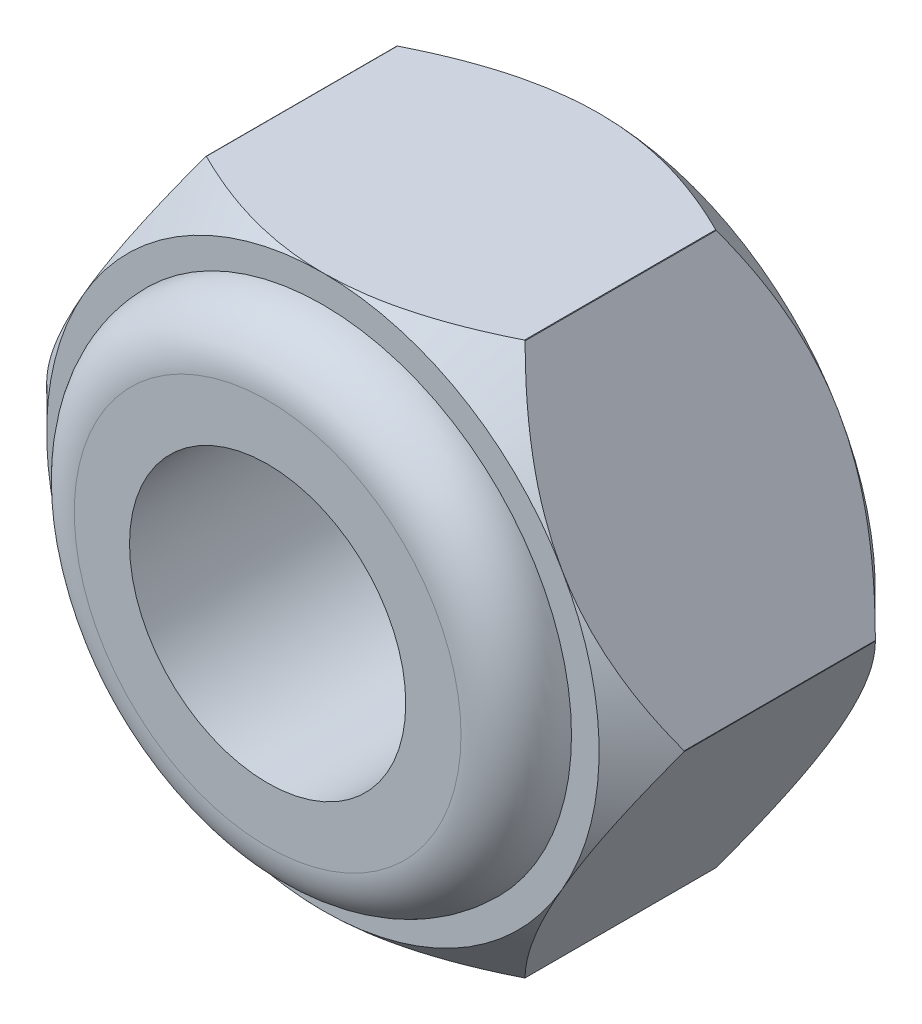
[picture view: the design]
ISO-10303-21;
HEADER;
FILE_DESCRIPTION(('STEP AP214'),'2;1');
FILE_NAME('part.step','',(''),(''),'','','');
FILE_SCHEMA(('AUTOMOTIVE_DESIGN { 1 0 10303 214 1 1 1 1 }'));
ENDSEC;
DATA;
#1=APPLICATION_CONTEXT('core data for automotive mechanical design processes');
#2=APPLICATION_PROTOCOL_DEFINITION('international standard','automotive_design',2000,#1);
#3=PRODUCT_CONTEXT('',#1,'mechanical');
#4=PRODUCT('Part','Part','',(#3));
#5=PRODUCT_RELATED_PRODUCT_CATEGORY('part','',(#4));
#6=PRODUCT_DEFINITION_FORMATION('','',#4);
#7=PRODUCT_DEFINITION_CONTEXT('part definition',#1,'design');
#8=PRODUCT_DEFINITION('design','',#6,#7);
#9=PRODUCT_DEFINITION_SHAPE('','',#8);
#10=(LENGTH_UNIT() NAMED_UNIT(*) SI_UNIT(.MILLI.,.METRE.));
#11=(NAMED_UNIT(*) PLANE_ANGLE_UNIT() SI_UNIT($,.RADIAN.));
#12=(NAMED_UNIT(*) SI_UNIT($,.STERADIAN.) SOLID_ANGLE_UNIT());
#13=UNCERTAINTY_MEASURE_WITH_UNIT(LENGTH_MEASURE(1.E-05),#10,'distance_accuracy_value','');
#14=(GEOMETRIC_REPRESENTATION_CONTEXT(3) GLOBAL_UNCERTAINTY_ASSIGNED_CONTEXT((#13)) GLOBAL_UNIT_ASSIGNED_CONTEXT((#10,
#11,#12)) REPRESENTATION_CONTEXT('',''));
#15=CARTESIAN_POINT('',(0.,0.,0.));
#16=DIRECTION('',(0.,0.,1.));
#17=DIRECTION('',(1.,0.,0.));
#18=AXIS2_PLACEMENT_3D('',#15,#16,#17);
#19=CARTESIAN_POINT('',(0.,0.,5.));
#20=DIRECTION('',(0.,0.,-1.));
#21=DIRECTION('',(-1.,0.,0.));
#22=AXIS2_PLACEMENT_3D('',#19,#20,#21);
#23=CYLINDRICAL_SURFACE('',#22,5.77);
#24=DIRECTION('',(0.,0.,-1.));
#25=VECTOR('',#24,1.);
#26=CARTESIAN_POINT('',(-2.89025723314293,4.99392762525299,5.));
#27=LINE('',#26,#25);
#28=CARTESIAN_POINT('',(-2.89025723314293,4.99392762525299,4.22999999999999));
#29=VERTEX_POINT('',#28);
#30=CARTESIAN_POINT('',(-2.89025723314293,4.99392762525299,0.770000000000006));
#31=VERTEX_POINT('',#30);
#32=EDGE_CURVE('E378',#29,#31,#27,.T.);
#33=ORIENTED_EDGE('',*,*,#32,.F.);
#34=CARTESIAN_POINT('',(0.,0.,4.22999999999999));
#35=DIRECTION('',(0.,0.,1.));
#36=DIRECTION('',(1.,0.,0.));
#37=AXIS2_PLACEMENT_3D('',#34,#35,#36);
#38=CIRCLE('',#37,5.77);
#39=CARTESIAN_POINT('',(-2.87973957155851,5.,4.22999999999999));
#40=VERTEX_POINT('',#39);
#41=EDGE_CURVE('E367',#29,#40,#38,.F.);
#42=ORIENTED_EDGE('',*,*,#41,.T.);
#43=DIRECTION('',(0.,0.,-1.));
#44=VECTOR('',#43,1.);
#45=CARTESIAN_POINT('',(-2.87973957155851,5.,5.));
#46=LINE('',#45,#44);
#47=CARTESIAN_POINT('',(-2.87973957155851,5.,0.770000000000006));
#48=VERTEX_POINT('',#47);
#49=EDGE_CURVE('E54',#48,#40,#46,.F.);
#50=ORIENTED_EDGE('',*,*,#49,.F.);
#51=CARTESIAN_POINT('',(0.,0.,0.770000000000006));
#52=DIRECTION('',(0.,0.,1.));
#53=DIRECTION('',(1.,0.,0.));
#54=AXIS2_PLACEMENT_3D('',#51,#52,#53);
#55=CIRCLE('',#54,5.77);
#56=EDGE_CURVE('E340',#48,#31,#55,.T.);
#57=ORIENTED_EDGE('',*,*,#56,.T.);
#58=EDGE_LOOP('',(#33,#42,#50,#57));
#59=FACE_BOUND('',#58,.T.);
#60=ADVANCED_FACE('F32',(#59),#23,.T.);
#61=DIRECTION('',(0.,0.,-1.));
#62=VECTOR('',#61,1.);
#63=CARTESIAN_POINT('',(-5.76999680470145,0.00607237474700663,5.));
#64=LINE('',#63,#62);
#65=CARTESIAN_POINT('',(-5.76999680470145,0.00607237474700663,0.770000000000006));
#66=VERTEX_POINT('',#65);
#67=CARTESIAN_POINT('',(-5.76999680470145,0.00607237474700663,4.22999999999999));
#68=VERTEX_POINT('',#67);
#69=EDGE_CURVE('E282',#66,#68,#64,.F.);
#70=ORIENTED_EDGE('',*,*,#69,.F.);
#71=CARTESIAN_POINT('',(-5.76999680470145,-0.00607237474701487,0.770000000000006));
#72=VERTEX_POINT('',#71);
#73=EDGE_CURVE('E345',#66,#72,#55,.T.);
#74=ORIENTED_EDGE('',*,*,#73,.T.);
#75=DIRECTION('',(0.,0.,-1.));
#76=VECTOR('',#75,1.);
#77=CARTESIAN_POINT('',(-5.76999680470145,-0.00607237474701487,5.));
#78=LINE('',#77,#76);
#79=CARTESIAN_POINT('',(-5.76999680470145,-0.00607237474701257,4.22999999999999));
#80=VERTEX_POINT('',#79);
#81=EDGE_CURVE('E231',#80,#72,#78,.T.);
#82=ORIENTED_EDGE('',*,*,#81,.F.);
#83=EDGE_CURVE('E177',#80,#68,#38,.F.);
#84=ORIENTED_EDGE('',*,*,#83,.T.);
#85=EDGE_LOOP('',(#70,#74,#82,#84));
#86=FACE_BOUND('',#85,.T.);
#87=ADVANCED_FACE('F399',(#86),#23,.T.);
#88=DIRECTION('',(0.,0.,-1.));
#89=VECTOR('',#88,1.);
#90=CARTESIAN_POINT('',(2.87973957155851,5.,5.));
#91=LINE('',#90,#89);
#92=CARTESIAN_POINT('',(2.87973957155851,5.,4.22999999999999));
#93=VERTEX_POINT('',#92);
#94=CARTESIAN_POINT('',(2.87973957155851,5.,0.770000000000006));
#95=VERTEX_POINT('',#94);
#96=EDGE_CURVE('E281',#93,#95,#91,.T.);
#97=ORIENTED_EDGE('',*,*,#96,.F.);
#98=CARTESIAN_POINT('',(2.89025723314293,4.99392762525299,4.22999999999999));
#99=VERTEX_POINT('',#98);
#100=EDGE_CURVE('E316',#93,#99,#38,.F.);
#101=ORIENTED_EDGE('',*,*,#100,.T.);
#102=DIRECTION('',(0.,0.,-1.));
#103=VECTOR('',#102,1.);
#104=CARTESIAN_POINT('',(2.89025723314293,4.99392762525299,5.));
#105=LINE('',#104,#103);
#106=CARTESIAN_POINT('',(2.89025723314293,4.99392762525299,0.770000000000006));
#107=VERTEX_POINT('',#106);
#108=EDGE_CURVE('E46',#107,#99,#105,.F.);
#109=ORIENTED_EDGE('',*,*,#108,.F.);
#110=EDGE_CURVE('E335',#107,#95,#55,.T.);
#111=ORIENTED_EDGE('',*,*,#110,.T.);
#112=EDGE_LOOP('',(#97,#101,#109,#111));
#113=FACE_BOUND('',#112,.T.);
#114=ADVANCED_FACE('F448',(#113),#23,.T.);
#115=DIRECTION('',(0.,0.,-1.));
#116=VECTOR('',#115,1.);
#117=CARTESIAN_POINT('',(5.76999680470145,0.00607237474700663,5.));
#118=LINE('',#117,#116);
#119=CARTESIAN_POINT('',(5.76999680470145,0.0060723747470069,4.22999999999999));
#120=VERTEX_POINT('',#119);
#121=CARTESIAN_POINT('',(5.76999680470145,0.00607237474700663,0.770000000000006));
#122=VERTEX_POINT('',#121);
#123=EDGE_CURVE('E402',#120,#122,#118,.T.);
#124=ORIENTED_EDGE('',*,*,#123,.F.);
#125=CARTESIAN_POINT('',(5.76999680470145,-0.00607237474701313,4.22999999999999));
#126=VERTEX_POINT('',#125);
#127=EDGE_CURVE('E358',#120,#126,#38,.F.);
#128=ORIENTED_EDGE('',*,*,#127,.T.);
#129=DIRECTION('',(0.,0.,-1.));
#130=VECTOR('',#129,1.);
#131=CARTESIAN_POINT('',(5.76999680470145,-0.00607237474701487,5.));
#132=LINE('',#131,#130);
#133=CARTESIAN_POINT('',(5.76999680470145,-0.00607237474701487,0.770000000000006));
#134=VERTEX_POINT('',#133);
#135=EDGE_CURVE('E410',#134,#126,#132,.F.);
#136=ORIENTED_EDGE('',*,*,#135,.F.);
#137=EDGE_CURVE('E341',#134,#122,#55,.T.);
#138=ORIENTED_EDGE('',*,*,#137,.T.);
#139=EDGE_LOOP('',(#124,#128,#136,#138));
#140=FACE_BOUND('',#139,.T.);
#141=ADVANCED_FACE('F454',(#140),#23,.T.);
#142=DIRECTION('',(0.,0.,-1.));
#143=VECTOR('',#142,1.);
#144=CARTESIAN_POINT('',(2.89025723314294,-4.99392762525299,5.));
#145=LINE('',#144,#143);
#146=CARTESIAN_POINT('',(2.89025723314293,-4.99392762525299,4.22999999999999));
#147=VERTEX_POINT('',#146);
#148=CARTESIAN_POINT('',(2.89025723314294,-4.99392762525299,0.770000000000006));
#149=VERTEX_POINT('',#148);
#150=EDGE_CURVE('E407',#147,#149,#145,.T.);
#151=ORIENTED_EDGE('',*,*,#150,.F.);
#152=CARTESIAN_POINT('',(2.87973957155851,-5.,4.22999999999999));
#153=VERTEX_POINT('',#152);
#154=EDGE_CURVE('E349',#147,#153,#38,.F.);
#155=ORIENTED_EDGE('',*,*,#154,.T.);
#156=DIRECTION('',(0.,0.,-1.));
#157=VECTOR('',#156,1.);
#158=CARTESIAN_POINT('',(2.87973957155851,-5.,5.));
#159=LINE('',#158,#157);
#160=CARTESIAN_POINT('',(2.87973957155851,-5.,0.770000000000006));
#161=VERTEX_POINT('',#160);
#162=EDGE_CURVE('E233',#161,#153,#159,.F.);
#163=ORIENTED_EDGE('',*,*,#162,.F.);
#164=EDGE_CURVE('E348',#161,#149,#55,.T.);
#165=ORIENTED_EDGE('',*,*,#164,.T.);
#166=EDGE_LOOP('',(#151,#155,#163,#165));
#167=FACE_BOUND('',#166,.T.);
#168=ADVANCED_FACE('F450',(#167),#23,.T.);
#169=DIRECTION('',(0.,0.,-1.));
#170=VECTOR('',#169,1.);
#171=CARTESIAN_POINT('',(-2.87973957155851,-5.,5.));
#172=LINE('',#171,#170);
#173=CARTESIAN_POINT('',(-2.87973957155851,-5.,4.22999999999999));
#174=VERTEX_POINT('',#173);
#175=CARTESIAN_POINT('',(-2.87973957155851,-5.,0.770000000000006));
#176=VERTEX_POINT('',#175);
#177=EDGE_CURVE('E415',#174,#176,#172,.T.);
#178=ORIENTED_EDGE('',*,*,#177,.F.);
#179=CARTESIAN_POINT('',(-2.89025723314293,-4.99392762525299,4.22999999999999));
#180=VERTEX_POINT('',#179);
#181=EDGE_CURVE('E357',#174,#180,#38,.F.);
#182=ORIENTED_EDGE('',*,*,#181,.T.);
#183=DIRECTION('',(0.,0.,-1.));
#184=VECTOR('',#183,1.);
#185=CARTESIAN_POINT('',(-2.89025723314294,-4.99392762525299,5.));
#186=LINE('',#185,#184);
#187=CARTESIAN_POINT('',(-2.89025723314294,-4.99392762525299,0.770000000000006));
#188=VERTEX_POINT('',#187);
#189=EDGE_CURVE('E161',#188,#180,#186,.F.);
#190=ORIENTED_EDGE('',*,*,#189,.F.);
#191=EDGE_CURVE('E355',#188,#176,#55,.T.);
#192=ORIENTED_EDGE('',*,*,#191,.T.);
#193=EDGE_LOOP('',(#178,#182,#190,#192));
#194=FACE_BOUND('',#193,.T.);
#195=ADVANCED_FACE('F240',(#194),#23,.T.);
#196=CARTESIAN_POINT('',(0.,0.,0.770000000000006));
#197=DIRECTION('',(0.,0.,1.));
#198=DIRECTION('',(1.,0.,0.));
#199=AXIS2_PLACEMENT_3D('',#196,#197,#198);
#200=CONICAL_SURFACE('',#199,5.77,0.785398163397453);
#201=ORIENTED_EDGE('',*,*,#73,.F.);
#202=CARTESIAN_POINT('',(-5.7702,0.0057204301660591,0.770202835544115));
#203=CARTESIAN_POINT('',(-5.72066643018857,0.0915150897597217,0.720761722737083));
#204=CARTESIAN_POINT('',(-5.67075262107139,0.177968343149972,0.672841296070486));
#205=CARTESIAN_POINT('',(-5.57009042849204,0.352320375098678,0.580503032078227));
#206=CARTESIAN_POINT('',(-5.51934160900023,0.440219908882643,0.536087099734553));
#207=CARTESIAN_POINT('',(-5.36526368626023,0.707090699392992,0.408412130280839));
#208=CARTESIAN_POINT('',(-5.26063326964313,0.888315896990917,0.331266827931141));
#209=CARTESIAN_POINT('',(-5.04964011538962,1.25376676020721,0.199176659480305));
#210=CARTESIAN_POINT('',(-4.94333082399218,1.43789985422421,0.143900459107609));
#211=CARTESIAN_POINT('',(-4.78212663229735,1.71711370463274,0.0799714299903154));
#212=CARTESIAN_POINT('',(-4.72815538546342,1.81059464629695,0.0618344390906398));
#213=CARTESIAN_POINT('',(-4.61975813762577,1.99834418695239,0.0322976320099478));
#214=CARTESIAN_POINT('',(-4.56533220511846,2.09261266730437,0.0208968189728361));
#215=CARTESIAN_POINT('',(-4.43253200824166,2.32262935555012,0.00176361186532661));
#216=CARTESIAN_POINT('',(-4.3540143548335,2.45862592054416,-0.00223001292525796));
#217=CARTESIAN_POINT('',(-4.19712243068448,2.7303707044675,0.00461104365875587));
#218=CARTESIAN_POINT('',(-4.11874821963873,2.86611882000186,0.0154509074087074));
#219=CARTESIAN_POINT('',(-3.96274074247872,3.13633169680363,0.0513199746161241));
#220=CARTESIAN_POINT('',(-3.88510839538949,3.27079486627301,0.0763649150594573));
#221=CARTESIAN_POINT('',(-3.73117872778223,3.53740887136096,0.139283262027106));
#222=CARTESIAN_POINT('',(-3.6548813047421,3.66955988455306,0.177155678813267));
#223=CARTESIAN_POINT('',(-3.51977568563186,3.90356968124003,0.254866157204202));
#224=CARTESIAN_POINT('',(-3.46066177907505,4.00595797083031,0.292618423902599));
#225=CARTESIAN_POINT('',(-3.3434891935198,4.20890684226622,0.374174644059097));
#226=CARTESIAN_POINT('',(-3.28543053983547,4.30946738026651,0.417978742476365));
#227=CARTESIAN_POINT('',(-3.17055191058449,4.50844300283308,0.510664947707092));
#228=CARTESIAN_POINT('',(-3.11372867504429,4.60686373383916,0.559531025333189));
#229=CARTESIAN_POINT('',(-3.00112820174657,4.80189347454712,0.661707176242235));
#230=CARTESIAN_POINT('',(-2.94535036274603,4.89850352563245,0.715014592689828));
#231=CARTESIAN_POINT('',(-2.89005687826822,4.99427465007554,0.770200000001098));
#232=B_SPLINE_CURVE_WITH_KNOTS('',3,(#202,#203,#204,#205,#206,#207,#208,#209,#210,#211,#212,
#213,#214,#215,#216,#217,#218,#219,#220,#221,#222,#223,#224,#225,#226,#227,#228,#229,#230,#231),
.UNSPECIFIED.,.F.,.F.,(4,2,2,2,2,2,2,2,2,2,2,2,2,2,4),(0.,0.332137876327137,0.664455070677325,
1.33265140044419,1.99029611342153,2.31847842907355,2.64661216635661,3.11713813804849,
3.58782853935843,4.05904141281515,4.53021793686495,4.90237265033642,5.27453627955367,
5.64555549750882,6.01635434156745),.UNSPECIFIED.);
#233=CARTESIAN_POINT('',(-4.33012701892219,2.5,0.));
#234=VERTEX_POINT('',#233);
#235=EDGE_CURVE('E369',#66,#234,#232,.T.);
#236=ORIENTED_EDGE('',*,*,#235,.T.);
#237=CARTESIAN_POINT('',(0.,0.,0.));
#238=DIRECTION('',(0.,0.,1.));
#239=DIRECTION('',(1.,0.,0.));
#240=AXIS2_PLACEMENT_3D('',#237,#238,#239);
#241=CIRCLE('',#240,4.99999999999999);
#242=CARTESIAN_POINT('',(-4.33012701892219,-2.5,0.));
#243=VERTEX_POINT('',#242);
#244=EDGE_CURVE('E333',#243,#234,#241,.F.);
#245=ORIENTED_EDGE('',*,*,#244,.F.);
#246=CARTESIAN_POINT('',(-2.89005687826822,-4.99427465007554,0.770200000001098));
#247=CARTESIAN_POINT('',(-2.93959036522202,-4.90848013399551,0.720759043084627));
#248=CARTESIAN_POINT('',(-2.98950409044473,-4.82202702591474,0.67283877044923));
#249=CARTESIAN_POINT('',(-3.09016611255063,-4.64767528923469,0.580500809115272));
#250=CARTESIAN_POINT('',(-3.1409148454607,-4.55977590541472,0.536085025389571));
#251=CARTESIAN_POINT('',(-3.294992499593,-4.29290558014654,0.408410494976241));
#252=CARTESIAN_POINT('',(-3.39962272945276,-4.11168070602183,0.331265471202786));
#253=CARTESIAN_POINT('',(-3.61061549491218,-3.74623051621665,0.199175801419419));
#254=CARTESIAN_POINT('',(-3.71692458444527,-3.56209777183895,0.143899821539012));
#255=CARTESIAN_POINT('',(-3.87812846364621,-3.28288446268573,0.0799710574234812));
#256=CARTESIAN_POINT('',(-3.93209960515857,-3.18940370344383,0.0618341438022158));
#257=CARTESIAN_POINT('',(-4.0404966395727,-3.00165453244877,0.032297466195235));
#258=CARTESIAN_POINT('',(-4.09492246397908,-2.9073862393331,0.0208967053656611));
#259=CARTESIAN_POINT('',(-4.22772254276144,-2.6773697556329,0.00176357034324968));
#260=CARTESIAN_POINT('',(-4.30624018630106,-2.54137320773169,-0.00223002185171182));
#261=CARTESIAN_POINT('',(-4.46313208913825,-2.26962846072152,0.00461109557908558));
#262=CARTESIAN_POINT('',(-4.54150628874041,-2.13388036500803,0.0154509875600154));
#263=CARTESIAN_POINT('',(-4.69751374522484,-1.86366752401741,0.0513201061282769));
#264=CARTESIAN_POINT('',(-4.77514608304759,-1.72920437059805,0.076365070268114));
#265=CARTESIAN_POINT('',(-4.92907573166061,-1.46259039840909,0.139283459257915));
#266=CARTESIAN_POINT('',(-5.00537314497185,-1.33043940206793,0.177155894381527));
#267=CARTESIAN_POINT('',(-5.14047897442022,-1.09642924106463,0.254866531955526));
#268=CARTESIAN_POINT('',(-5.19959309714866,-0.994040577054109,0.292618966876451));
#269=CARTESIAN_POINT('',(-5.31676610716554,-0.791090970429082,0.374175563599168));
#270=CARTESIAN_POINT('',(-5.37482496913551,-0.690530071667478,0.417979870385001));
#271=CARTESIAN_POINT('',(-5.48970400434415,-0.491553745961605,0.510666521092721));
#272=CARTESIAN_POINT('',(-5.5465274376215,-0.393132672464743,0.559532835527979));
#273=CARTESIAN_POINT('',(-5.65912829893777,-0.198102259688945,0.661709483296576));
#274=CARTESIAN_POINT('',(-5.71490632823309,-0.101491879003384,0.715017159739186));
#275=CARTESIAN_POINT('',(-5.7702,-0.00572043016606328,0.770202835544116));
#276=B_SPLINE_CURVE_WITH_KNOTS('',3,(#246,#247,#248,#249,#250,#251,#252,#253,#254,#255,#256,
#257,#258,#259,#260,#261,#262,#263,#264,#265,#266,#267,#268,#269,#270,#271,#272,#273,#274,#275),
.UNSPECIFIED.,.F.,.F.,(4,2,2,2,2,2,2,2,2,2,2,2,2,2,4),(0.,0.332137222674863,0.664453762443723,
1.33264875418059,1.99029213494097,2.31847378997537,2.64660686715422,3.11713277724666,
3.58782311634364,4.05903594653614,4.53021242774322,4.90236852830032,5.27453354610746,
5.64555413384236,6.01635434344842),.UNSPECIFIED.);
#277=EDGE_CURVE('E223',#243,#72,#276,.T.);
#278=ORIENTED_EDGE('',*,*,#277,.T.);
#279=EDGE_LOOP('',(#201,#236,#245,#278));
#280=FACE_BOUND('',#279,.T.);
#281=ADVANCED_FACE('F235',(#280),#200,.T.);
#282=CARTESIAN_POINT('',(0.,5.,0.));
#283=VERTEX_POINT('',#282);
#284=EDGE_CURVE('E338',#234,#283,#241,.F.);
#285=ORIENTED_EDGE('',*,*,#284,.F.);
#286=EDGE_CURVE('E373',#234,#31,#232,.T.);
#287=ORIENTED_EDGE('',*,*,#286,.T.);
#288=ORIENTED_EDGE('',*,*,#56,.F.);
#289=CARTESIAN_POINT('',(-6.0229983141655,5.,2.82793131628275));
#290=CARTESIAN_POINT('',(-5.87748004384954,5.,2.71599120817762));
#291=CARTESIAN_POINT('',(-5.73117753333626,5.,2.60505456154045));
#292=CARTESIAN_POINT('',(-5.43668354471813,5.,2.38564658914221));
#293=CARTESIAN_POINT('',(-5.28849162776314,5.,2.27717585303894));
#294=CARTESIAN_POINT('',(-4.98881537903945,5.,2.06238616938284));
#295=CARTESIAN_POINT('',(-4.83731446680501,5.,1.95609027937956));
#296=CARTESIAN_POINT('',(-4.53179094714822,5.,1.7471989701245));
#297=CARTESIAN_POINT('',(-4.37776851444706,5.,1.64460329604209));
#298=CARTESIAN_POINT('',(-4.05692316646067,5.,1.43759704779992));
#299=CARTESIAN_POINT('',(-3.88990763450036,5.,1.33348351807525));
#300=CARTESIAN_POINT('',(-3.55195456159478,5.,1.13172056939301));
#301=CARTESIAN_POINT('',(-3.38101636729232,5.,1.03407223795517));
#302=CARTESIAN_POINT('',(-3.03517153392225,5.,0.847319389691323));
#303=CARTESIAN_POINT('',(-2.86027854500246,5.,0.75818979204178));
#304=CARTESIAN_POINT('',(-2.5055493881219,5.,0.590471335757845));
#305=CARTESIAN_POINT('',(-2.32571560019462,5.,0.51187750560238));
#306=CARTESIAN_POINT('',(-1.97870613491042,5.,0.375168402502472));
#307=CARTESIAN_POINT('',(-1.81202993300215,5.,0.315798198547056));
#308=CARTESIAN_POINT('',(-1.47443232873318,5.,0.210399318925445));
#309=CARTESIAN_POINT('',(-1.3035106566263,5.,0.164371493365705));
#310=CARTESIAN_POINT('',(-0.961419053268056,5.,0.0889155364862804));
#311=CARTESIAN_POINT('',(-0.790316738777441,5.,0.0591860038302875));
#312=CARTESIAN_POINT('',(-0.44598784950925,5.,0.0169466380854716));
#313=CARTESIAN_POINT('',(-0.272761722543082,5.,0.00443323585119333));
#314=CARTESIAN_POINT('',(0.0664794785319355,5.,-0.00230866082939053));
#315=CARTESIAN_POINT('',(0.232479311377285,5.,0.00268865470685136));
#316=CARTESIAN_POINT('',(0.563182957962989,5.,0.0289153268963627));
#317=CARTESIAN_POINT('',(0.727886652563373,5.,0.0501461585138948));
#318=CARTESIAN_POINT('',(1.05759729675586,5.,0.108000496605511));
#319=CARTESIAN_POINT('',(1.22255575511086,5.,0.144895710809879));
#320=CARTESIAN_POINT('',(1.54884022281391,5.,0.232032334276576));
#321=CARTESIAN_POINT('',(1.71016643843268,5.,0.28227298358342));
#322=CARTESIAN_POINT('',(2.03810171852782,5.,0.397120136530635));
#323=CARTESIAN_POINT('',(2.20447580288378,5.,0.462390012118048));
#324=CARTESIAN_POINT('',(2.53294434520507,5.,0.603013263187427));
#325=CARTESIAN_POINT('',(2.69503683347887,5.,0.678371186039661));
#326=CARTESIAN_POINT('',(3.01570779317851,5.,0.837383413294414));
#327=CARTESIAN_POINT('',(3.17427348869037,5.,0.921063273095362));
#328=CARTESIAN_POINT('',(3.48777135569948,5.,1.09487786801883));
#329=CARTESIAN_POINT('',(3.64270408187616,5.,1.18501160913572));
#330=CARTESIAN_POINT('',(3.94183849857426,5.,1.36589469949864));
#331=CARTESIAN_POINT('',(4.08619228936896,5.,1.45639384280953));
#332=CARTESIAN_POINT('',(4.37241977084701,5.,1.64124403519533));
#333=CARTESIAN_POINT('',(4.51429327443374,5.,1.73559537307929));
#334=CARTESIAN_POINT('',(4.79474397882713,5.,1.92669485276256));
#335=CARTESIAN_POINT('',(4.93333850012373,5.,2.02341766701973));
#336=CARTESIAN_POINT('',(5.20862624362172,5.,2.21945594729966));
#337=CARTESIAN_POINT('',(5.34531997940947,5.,2.31877069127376));
#338=CARTESIAN_POINT('',(5.48121637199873,5.,2.41914637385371));
#339=B_SPLINE_CURVE_WITH_KNOTS('',3,(#289,#290,#291,#292,#293,#294,#295,#296,#297,#298,#299,
#300,#301,#302,#303,#304,#305,#306,#307,#308,#309,#310,#311,#312,#313,#314,#315,#316,#317,#318,
#319,#320,#321,#322,#323,#324,#325,#326,#327,#328,#329,#330,#331,#332,#333,#334,#335,#336,#337,
#338),.UNSPECIFIED.,.F.,.F.,(4,2,2,2,2,2,2,2,2,2,2,2,2,2,2,2,2,2,2,2,2,2,2,2,4),(0.,
0.550787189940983,1.10170472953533,1.65687262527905,2.21200221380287,2.80231311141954,
3.39272305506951,3.98133740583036,4.56967302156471,5.10001866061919,5.63039808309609,
6.15060655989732,6.67070717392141,7.16810854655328,7.66555511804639,8.17200736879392,
8.67843078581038,9.21417708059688,9.75016569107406,10.2878542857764,10.825460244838,
11.3365177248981,11.84761359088,12.3546057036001,12.861458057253),.UNSPECIFIED.);
#340=EDGE_CURVE('E280',#48,#283,#339,.T.);
#341=ORIENTED_EDGE('',*,*,#340,.T.);
#342=EDGE_LOOP('',(#285,#287,#288,#341));
#343=FACE_BOUND('',#342,.T.);
#344=ADVANCED_FACE('F239',(#343),#200,.T.);
#345=CARTESIAN_POINT('',(4.33012701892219,2.5,0.));
#346=VERTEX_POINT('',#345);
#347=EDGE_CURVE('E334',#283,#346,#241,.F.);
#348=ORIENTED_EDGE('',*,*,#347,.F.);
#349=EDGE_CURVE('E272',#283,#95,#339,.T.);
#350=ORIENTED_EDGE('',*,*,#349,.T.);
#351=ORIENTED_EDGE('',*,*,#110,.F.);
#352=CARTESIAN_POINT('',(2.89005687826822,4.99427465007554,0.770200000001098));
#353=CARTESIAN_POINT('',(2.93959036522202,4.90848013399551,0.720759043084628));
#354=CARTESIAN_POINT('',(2.98950409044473,4.82202702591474,0.67283877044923));
#355=CARTESIAN_POINT('',(3.09016611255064,4.64767528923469,0.580500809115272));
#356=CARTESIAN_POINT('',(3.1409148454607,4.55977590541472,0.53608502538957));
#357=CARTESIAN_POINT('',(3.294992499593,4.29290558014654,0.40841049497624));
#358=CARTESIAN_POINT('',(3.39962272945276,4.11168070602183,0.331265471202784));
#359=CARTESIAN_POINT('',(3.61061549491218,3.74623051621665,0.199175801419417));
#360=CARTESIAN_POINT('',(3.71692458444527,3.56209777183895,0.143899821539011));
#361=CARTESIAN_POINT('',(3.87812846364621,3.28288446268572,0.0799710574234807));
#362=CARTESIAN_POINT('',(3.93209960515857,3.18940370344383,0.0618341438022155));
#363=CARTESIAN_POINT('',(4.0404966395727,3.00165453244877,0.0322974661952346));
#364=CARTESIAN_POINT('',(4.09492246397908,2.9073862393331,0.0208967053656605));
#365=CARTESIAN_POINT('',(4.22772254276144,2.6773697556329,0.00176357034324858));
#366=CARTESIAN_POINT('',(4.30624018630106,2.54137320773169,-0.00223002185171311));
#367=CARTESIAN_POINT('',(4.46313208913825,2.26962846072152,0.00461109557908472));
#368=CARTESIAN_POINT('',(4.54150628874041,2.13388036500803,0.0154509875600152));
#369=CARTESIAN_POINT('',(4.69751374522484,1.8636675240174,0.0513201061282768));
#370=CARTESIAN_POINT('',(4.77514608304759,1.72920437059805,0.0763650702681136));
#371=CARTESIAN_POINT('',(4.92907573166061,1.46259039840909,0.139283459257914));
#372=CARTESIAN_POINT('',(5.00537314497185,1.33043940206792,0.177155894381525));
#373=CARTESIAN_POINT('',(5.14047897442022,1.09642924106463,0.254866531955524));
#374=CARTESIAN_POINT('',(5.19959309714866,0.994040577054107,0.29261896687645));
#375=CARTESIAN_POINT('',(5.31676610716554,0.791090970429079,0.374175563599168));
#376=CARTESIAN_POINT('',(5.37482496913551,0.690530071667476,0.417979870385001));
#377=CARTESIAN_POINT('',(5.48970400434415,0.491553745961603,0.510666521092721));
#378=CARTESIAN_POINT('',(5.5465274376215,0.39313267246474,0.559532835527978));
#379=CARTESIAN_POINT('',(5.65912829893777,0.198102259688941,0.661709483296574));
#380=CARTESIAN_POINT('',(5.71490632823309,0.101491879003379,0.715017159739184));
#381=CARTESIAN_POINT('',(5.7702,0.00572043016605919,0.770202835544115));
#382=B_SPLINE_CURVE_WITH_KNOTS('',3,(#352,#353,#354,#355,#356,#357,#358,#359,#360,#361,#362,
#363,#364,#365,#366,#367,#368,#369,#370,#371,#372,#373,#374,#375,#376,#377,#378,#379,#380,#381),
.UNSPECIFIED.,.F.,.F.,(4,2,2,2,2,2,2,2,2,2,2,2,2,2,4),(0.,0.332137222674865,0.664453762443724,
1.33264875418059,1.99029213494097,2.31847378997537,2.64660686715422,3.11713277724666,
3.58782311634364,4.05903594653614,4.53021242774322,4.90236852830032,5.27453354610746,
5.64555413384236,6.01635434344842),.UNSPECIFIED.);
#383=EDGE_CURVE('E392',#107,#346,#382,.T.);
#384=ORIENTED_EDGE('',*,*,#383,.T.);
#385=EDGE_LOOP('',(#348,#350,#351,#384));
#386=FACE_BOUND('',#385,.T.);
#387=ADVANCED_FACE('F391',(#386),#200,.T.);
#388=CARTESIAN_POINT('',(4.33012701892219,-2.5,0.));
#389=VERTEX_POINT('',#388);
#390=EDGE_CURVE('E328',#346,#389,#241,.F.);
#391=ORIENTED_EDGE('',*,*,#390,.F.);
#392=EDGE_CURVE('E264',#346,#122,#382,.T.);
#393=ORIENTED_EDGE('',*,*,#392,.T.);
#394=ORIENTED_EDGE('',*,*,#137,.F.);
#395=CARTESIAN_POINT('',(5.7702,-0.00572043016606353,0.770202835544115));
#396=CARTESIAN_POINT('',(5.72066643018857,-0.0915150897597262,0.720761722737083));
#397=CARTESIAN_POINT('',(5.67075262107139,-0.177968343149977,0.672841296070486));
#398=CARTESIAN_POINT('',(5.57009042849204,-0.352320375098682,0.580503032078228));
#399=CARTESIAN_POINT('',(5.51934160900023,-0.440219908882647,0.536087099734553));
#400=CARTESIAN_POINT('',(5.36526368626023,-0.707090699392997,0.40841213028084));
#401=CARTESIAN_POINT('',(5.26063326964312,-0.888315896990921,0.331266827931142));
#402=CARTESIAN_POINT('',(5.04964011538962,-1.25376676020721,0.199176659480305));
#403=CARTESIAN_POINT('',(4.94333082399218,-1.43789985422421,0.14390045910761));
#404=CARTESIAN_POINT('',(4.78212663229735,-1.71711370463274,0.0799714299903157));
#405=CARTESIAN_POINT('',(4.72815538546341,-1.81059464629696,0.06183443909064));
#406=CARTESIAN_POINT('',(4.61975813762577,-1.99834418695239,0.0322976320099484));
#407=CARTESIAN_POINT('',(4.56533220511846,-2.09261266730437,0.0208968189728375));
#408=CARTESIAN_POINT('',(4.43253200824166,-2.32262935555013,0.0017636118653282));
#409=CARTESIAN_POINT('',(4.35401435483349,-2.45862592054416,-0.00223001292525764));
#410=CARTESIAN_POINT('',(4.19712243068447,-2.7303707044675,0.00461104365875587));
#411=CARTESIAN_POINT('',(4.11874821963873,-2.86611882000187,0.0154509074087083));
#412=CARTESIAN_POINT('',(3.96274074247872,-3.13633169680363,0.0513199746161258));
#413=CARTESIAN_POINT('',(3.88510839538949,-3.27079486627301,0.0763649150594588));
#414=CARTESIAN_POINT('',(3.73117872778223,-3.53740887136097,0.139283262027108));
#415=CARTESIAN_POINT('',(3.65488130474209,-3.66955988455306,0.177155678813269));
#416=CARTESIAN_POINT('',(3.51977568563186,-3.90356968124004,0.254866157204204));
#417=CARTESIAN_POINT('',(3.46066177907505,-4.00595797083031,0.2926184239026));
#418=CARTESIAN_POINT('',(3.34348919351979,-4.20890684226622,0.374174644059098));
#419=CARTESIAN_POINT('',(3.28543053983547,-4.30946738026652,0.417978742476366));
#420=CARTESIAN_POINT('',(3.17055191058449,-4.50844300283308,0.510664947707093));
#421=CARTESIAN_POINT('',(3.11372867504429,-4.60686373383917,0.55953102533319));
#422=CARTESIAN_POINT('',(3.00112820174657,-4.80189347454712,0.661707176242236));
#423=CARTESIAN_POINT('',(2.94535036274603,-4.89850352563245,0.715014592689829));
#424=CARTESIAN_POINT('',(2.89005687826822,-4.99427465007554,0.770200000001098));
#425=B_SPLINE_CURVE_WITH_KNOTS('',3,(#395,#396,#397,#398,#399,#400,#401,#402,#403,#404,#405,
#406,#407,#408,#409,#410,#411,#412,#413,#414,#415,#416,#417,#418,#419,#420,#421,#422,#423,#424),
.UNSPECIFIED.,.F.,.F.,(4,2,2,2,2,2,2,2,2,2,2,2,2,2,4),(0.,0.332137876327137,0.664455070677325,
1.33265140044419,1.99029611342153,2.31847842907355,2.64661216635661,3.11713813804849,
3.58782853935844,4.05904141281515,4.53021793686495,4.90237265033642,5.27453627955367,
5.64555549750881,6.01635434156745),.UNSPECIFIED.);
#426=EDGE_CURVE('E404',#134,#389,#425,.T.);
#427=ORIENTED_EDGE('',*,*,#426,.T.);
#428=EDGE_LOOP('',(#391,#393,#394,#427));
#429=FACE_BOUND('',#428,.T.);
#430=ADVANCED_FACE('F539',(#429),#200,.T.);
#431=CARTESIAN_POINT('',(0.,-5.,0.));
#432=VERTEX_POINT('',#431);
#433=EDGE_CURVE('E196',#389,#432,#241,.F.);
#434=ORIENTED_EDGE('',*,*,#433,.F.);
#435=EDGE_CURVE('E257',#389,#149,#425,.T.);
#436=ORIENTED_EDGE('',*,*,#435,.T.);
#437=ORIENTED_EDGE('',*,*,#164,.F.);
#438=CARTESIAN_POINT('',(-6.02299831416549,-5.,2.82793131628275));
#439=CARTESIAN_POINT('',(-5.87748004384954,-5.,2.71599120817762));
#440=CARTESIAN_POINT('',(-5.73117753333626,-5.,2.60505456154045));
#441=CARTESIAN_POINT('',(-5.43668354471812,-5.,2.38564658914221));
#442=CARTESIAN_POINT('',(-5.28849162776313,-5.,2.27717585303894));
#443=CARTESIAN_POINT('',(-4.98881537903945,-5.,2.06238616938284));
#444=CARTESIAN_POINT('',(-4.837314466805,-5.,1.95609027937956));
#445=CARTESIAN_POINT('',(-4.53179094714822,-5.,1.7471989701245));
#446=CARTESIAN_POINT('',(-4.37776851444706,-5.,1.64460329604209));
#447=CARTESIAN_POINT('',(-4.05692316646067,-5.,1.43759704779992));
#448=CARTESIAN_POINT('',(-3.88990763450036,-5.,1.33348351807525));
#449=CARTESIAN_POINT('',(-3.55195456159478,-5.,1.13172056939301));
#450=CARTESIAN_POINT('',(-3.38101636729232,-5.,1.03407223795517));
#451=CARTESIAN_POINT('',(-3.03517153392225,-5.,0.847319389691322));
#452=CARTESIAN_POINT('',(-2.86027854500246,-5.,0.75818979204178));
#453=CARTESIAN_POINT('',(-2.5055493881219,-5.,0.590471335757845));
#454=CARTESIAN_POINT('',(-2.32571560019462,-5.,0.51187750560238));
#455=CARTESIAN_POINT('',(-1.97870613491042,-5.,0.375168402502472));
#456=CARTESIAN_POINT('',(-1.81202993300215,-5.,0.315798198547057));
#457=CARTESIAN_POINT('',(-1.47443232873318,-5.,0.210399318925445));
#458=CARTESIAN_POINT('',(-1.3035106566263,-5.,0.164371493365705));
#459=CARTESIAN_POINT('',(-0.961419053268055,-5.,0.0889155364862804));
#460=CARTESIAN_POINT('',(-0.79031673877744,-5.,0.0591860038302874));
#461=CARTESIAN_POINT('',(-0.44598784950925,-5.,0.0169466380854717));
#462=CARTESIAN_POINT('',(-0.272761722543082,-5.,0.00443323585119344));
#463=CARTESIAN_POINT('',(0.0664794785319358,-5.,-0.00230866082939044));
#464=CARTESIAN_POINT('',(0.232479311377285,-5.,0.00268865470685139));
#465=CARTESIAN_POINT('',(0.56318295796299,-5.,0.0289153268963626));
#466=CARTESIAN_POINT('',(0.727886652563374,-5.,0.0501461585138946));
#467=CARTESIAN_POINT('',(1.05759729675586,-5.,0.10800049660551));
#468=CARTESIAN_POINT('',(1.22255575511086,-5.,0.144895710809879));
#469=CARTESIAN_POINT('',(1.54884022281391,-5.,0.232032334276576));
#470=CARTESIAN_POINT('',(1.71016643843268,-5.,0.28227298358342));
#471=CARTESIAN_POINT('',(2.03810171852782,-5.,0.397120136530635));
#472=CARTESIAN_POINT('',(2.20447580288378,-5.,0.462390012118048));
#473=CARTESIAN_POINT('',(2.53294434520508,-5.,0.603013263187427));
#474=CARTESIAN_POINT('',(2.69503683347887,-5.,0.678371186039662));
#475=CARTESIAN_POINT('',(3.01570779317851,-5.,0.837383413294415));
#476=CARTESIAN_POINT('',(3.17427348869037,-5.,0.921063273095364));
#477=CARTESIAN_POINT('',(3.48777135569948,-5.,1.09487786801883));
#478=CARTESIAN_POINT('',(3.64270408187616,-5.,1.18501160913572));
#479=CARTESIAN_POINT('',(3.94183849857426,-5.,1.36589469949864));
#480=CARTESIAN_POINT('',(4.08619228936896,-5.,1.45639384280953));
#481=CARTESIAN_POINT('',(4.37241977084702,-5.,1.64124403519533));
#482=CARTESIAN_POINT('',(4.51429327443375,-5.,1.7355953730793));
#483=CARTESIAN_POINT('',(4.79474397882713,-5.,1.92669485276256));
#484=CARTESIAN_POINT('',(4.93333850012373,-5.,2.02341766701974));
#485=CARTESIAN_POINT('',(5.20862624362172,-5.,2.21945594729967));
#486=CARTESIAN_POINT('',(5.34531997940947,-5.,2.31877069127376));
#487=CARTESIAN_POINT('',(5.48121637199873,-5.,2.41914637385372));
#488=B_SPLINE_CURVE_WITH_KNOTS('',3,(#438,#439,#440,#441,#442,#443,#444,#445,#446,#447,#448,
#449,#450,#451,#452,#453,#454,#455,#456,#457,#458,#459,#460,#461,#462,#463,#464,#465,#466,#467,
#468,#469,#470,#471,#472,#473,#474,#475,#476,#477,#478,#479,#480,#481,#482,#483,#484,#485,#486,
#487),.UNSPECIFIED.,.F.,.F.,(4,2,2,2,2,2,2,2,2,2,2,2,2,2,2,2,2,2,2,2,2,2,2,2,4),(0.,
0.550787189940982,1.10170472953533,1.65687262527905,2.21200221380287,2.80231311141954,
3.39272305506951,3.98133740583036,4.56967302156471,5.10001866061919,5.63039808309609,
6.15060655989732,6.6707071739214,7.16810854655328,7.66555511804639,8.17200736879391,
8.67843078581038,9.21417708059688,9.75016569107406,10.2878542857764,10.825460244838,
11.3365177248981,11.84761359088,12.3546057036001,12.861458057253),.UNSPECIFIED.);
#489=EDGE_CURVE('E412',#161,#432,#488,.F.);
#490=ORIENTED_EDGE('',*,*,#489,.T.);
#491=EDGE_LOOP('',(#434,#436,#437,#490));
#492=FACE_BOUND('',#491,.T.);
#493=ADVANCED_FACE('F533',(#492),#200,.T.);
#494=EDGE_CURVE('E327',#432,#243,#241,.F.);
#495=ORIENTED_EDGE('',*,*,#494,.F.);
#496=EDGE_CURVE('E250',#432,#176,#488,.F.);
#497=ORIENTED_EDGE('',*,*,#496,.T.);
#498=ORIENTED_EDGE('',*,*,#191,.F.);
#499=EDGE_CURVE('E230',#188,#243,#276,.T.);
#500=ORIENTED_EDGE('',*,*,#499,.T.);
#501=EDGE_LOOP('',(#495,#497,#498,#500));
#502=FACE_BOUND('',#501,.T.);
#503=ADVANCED_FACE('F242',(#502),#200,.T.);
#504=CARTESIAN_POINT('',(0.,0.,5.));
#505=DIRECTION('',(0.,0.,-1.));
#506=DIRECTION('',(-1.,0.,0.));
#507=AXIS2_PLACEMENT_3D('',#504,#505,#506);
#508=CONICAL_SURFACE('',#507,4.99999999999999,0.785398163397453);
#509=ORIENTED_EDGE('',*,*,#41,.F.);
#510=CARTESIAN_POINT('',(-2.89005687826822,4.99427465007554,4.2297999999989));
#511=CARTESIAN_POINT('',(-2.93959036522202,4.90848013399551,4.27924095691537));
#512=CARTESIAN_POINT('',(-2.98950409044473,4.82202702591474,4.32716122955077));
#513=CARTESIAN_POINT('',(-3.09016611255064,4.64767528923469,4.41949919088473));
#514=CARTESIAN_POINT('',(-3.1409148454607,4.55977590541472,4.46391497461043));
#515=CARTESIAN_POINT('',(-3.294992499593,4.29290558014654,4.59158950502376));
#516=CARTESIAN_POINT('',(-3.39962272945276,4.11168070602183,4.66873452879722));
#517=CARTESIAN_POINT('',(-3.61061549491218,3.74623051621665,4.80082419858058));
#518=CARTESIAN_POINT('',(-3.71692458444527,3.56209777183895,4.85610017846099));
#519=CARTESIAN_POINT('',(-3.87812846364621,3.28288446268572,4.92002894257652));
#520=CARTESIAN_POINT('',(-3.93209960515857,3.18940370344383,4.93816585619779));
#521=CARTESIAN_POINT('',(-4.0404966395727,3.00165453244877,4.96770253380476));
#522=CARTESIAN_POINT('',(-4.09492246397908,2.9073862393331,4.97910329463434));
#523=CARTESIAN_POINT('',(-4.22772254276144,2.6773697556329,4.99823642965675));
#524=CARTESIAN_POINT('',(-4.30624018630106,2.54137320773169,5.00223002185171));
#525=CARTESIAN_POINT('',(-4.46313208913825,2.26962846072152,4.99538890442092));
#526=CARTESIAN_POINT('',(-4.54150628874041,2.13388036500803,4.98454901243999));
#527=CARTESIAN_POINT('',(-4.69751374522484,1.8636675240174,4.94867989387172));
#528=CARTESIAN_POINT('',(-4.77514608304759,1.72920437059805,4.92363492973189));
#529=CARTESIAN_POINT('',(-4.92907573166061,1.46259039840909,4.86071654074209));
#530=CARTESIAN_POINT('',(-5.00537314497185,1.33043940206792,4.82284410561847));
#531=CARTESIAN_POINT('',(-5.14047897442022,1.09642924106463,4.74513346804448));
#532=CARTESIAN_POINT('',(-5.19959309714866,0.994040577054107,4.70738103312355));
#533=CARTESIAN_POINT('',(-5.31676610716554,0.791090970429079,4.62582443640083));
#534=CARTESIAN_POINT('',(-5.37482496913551,0.690530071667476,4.582020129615));
#535=CARTESIAN_POINT('',(-5.48970400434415,0.491553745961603,4.48933347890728));
#536=CARTESIAN_POINT('',(-5.5465274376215,0.39313267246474,4.44046716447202));
#537=CARTESIAN_POINT('',(-5.65912829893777,0.198102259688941,4.33829051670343));
#538=CARTESIAN_POINT('',(-5.71490632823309,0.101491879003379,4.28498284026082));
#539=CARTESIAN_POINT('',(-5.7702,0.00572043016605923,4.22979716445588));
#540=B_SPLINE_CURVE_WITH_KNOTS('',3,(#510,#511,#512,#513,#514,#515,#516,#517,#518,#519,#520,
#521,#522,#523,#524,#525,#526,#527,#528,#529,#530,#531,#532,#533,#534,#535,#536,#537,#538,#539),
.UNSPECIFIED.,.F.,.F.,(4,2,2,2,2,2,2,2,2,2,2,2,2,2,4),(0.,0.332137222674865,0.664453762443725,
1.33264875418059,1.99029213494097,2.31847378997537,2.64660686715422,3.11713277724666,
3.58782311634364,4.05903594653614,4.53021242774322,4.90236852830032,5.27453354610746,
5.64555413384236,6.01635434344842),.UNSPECIFIED.);
#541=CARTESIAN_POINT('',(-4.33012701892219,2.5,5.));
#542=VERTEX_POINT('',#541);
#543=EDGE_CURVE('E39',#29,#542,#540,.T.);
#544=ORIENTED_EDGE('',*,*,#543,.T.);
#545=CARTESIAN_POINT('',(0.,0.,5.));
#546=DIRECTION('',(0.,0.,1.));
#547=DIRECTION('',(1.,0.,0.));
#548=AXIS2_PLACEMENT_3D('',#545,#546,#547);
#549=CIRCLE('',#548,4.99999999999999);
#550=CARTESIAN_POINT('',(0.,5.,5.));
#551=VERTEX_POINT('',#550);
#552=EDGE_CURVE('E193',#551,#542,#549,.T.);
#553=ORIENTED_EDGE('',*,*,#552,.F.);
#554=CARTESIAN_POINT('',(-6.02299831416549,5.,2.17206868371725));
#555=CARTESIAN_POINT('',(-5.87748004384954,5.,2.28400879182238));
#556=CARTESIAN_POINT('',(-5.73117753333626,5.,2.39494543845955));
#557=CARTESIAN_POINT('',(-5.43668354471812,5.,2.61435341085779));
#558=CARTESIAN_POINT('',(-5.28849162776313,5.,2.72282414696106));
#559=CARTESIAN_POINT('',(-4.98881537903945,5.,2.93761383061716));
#560=CARTESIAN_POINT('',(-4.837314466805,5.,3.04390972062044));
#561=CARTESIAN_POINT('',(-4.53179094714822,5.,3.2528010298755));
#562=CARTESIAN_POINT('',(-4.37776851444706,5.,3.35539670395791));
#563=CARTESIAN_POINT('',(-4.05692316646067,5.,3.56240295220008));
#564=CARTESIAN_POINT('',(-3.88990763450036,5.,3.66651648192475));
#565=CARTESIAN_POINT('',(-3.55195456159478,5.,3.86827943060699));
#566=CARTESIAN_POINT('',(-3.38101636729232,5.,3.96592776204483));
#567=CARTESIAN_POINT('',(-3.03517153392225,5.,4.15268061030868));
#568=CARTESIAN_POINT('',(-2.86027854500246,5.,4.24181020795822));
#569=CARTESIAN_POINT('',(-2.5055493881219,5.,4.40952866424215));
#570=CARTESIAN_POINT('',(-2.32571560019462,5.,4.48812249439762));
#571=CARTESIAN_POINT('',(-1.97870613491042,5.,4.62483159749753));
#572=CARTESIAN_POINT('',(-1.81202993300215,5.,4.68420180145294));
#573=CARTESIAN_POINT('',(-1.47443232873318,5.,4.78960068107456));
#574=CARTESIAN_POINT('',(-1.3035106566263,5.,4.8356285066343));
#575=CARTESIAN_POINT('',(-0.961419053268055,5.,4.91108446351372));
#576=CARTESIAN_POINT('',(-0.79031673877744,5.,4.94081399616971));
#577=CARTESIAN_POINT('',(-0.44598784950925,5.,4.98305336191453));
#578=CARTESIAN_POINT('',(-0.272761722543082,5.,4.99556676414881));
#579=CARTESIAN_POINT('',(0.0664794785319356,5.,5.00230866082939));
#580=CARTESIAN_POINT('',(0.232479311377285,5.,4.99731134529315));
#581=CARTESIAN_POINT('',(0.56318295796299,5.,4.97108467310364));
#582=CARTESIAN_POINT('',(0.727886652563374,5.,4.94985384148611));
#583=CARTESIAN_POINT('',(1.05759729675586,5.,4.89199950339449));
#584=CARTESIAN_POINT('',(1.22255575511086,5.,4.85510428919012));
#585=CARTESIAN_POINT('',(1.54884022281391,5.,4.76796766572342));
#586=CARTESIAN_POINT('',(1.71016643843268,5.,4.71772701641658));
#587=CARTESIAN_POINT('',(2.03810171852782,5.,4.60287986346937));
#588=CARTESIAN_POINT('',(2.20447580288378,5.,4.53760998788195));
#589=CARTESIAN_POINT('',(2.53294434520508,5.,4.39698673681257));
#590=CARTESIAN_POINT('',(2.69503683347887,5.,4.32162881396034));
#591=CARTESIAN_POINT('',(3.01570779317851,5.,4.16261658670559));
#592=CARTESIAN_POINT('',(3.17427348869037,5.,4.07893672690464));
#593=CARTESIAN_POINT('',(3.48777135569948,5.,3.90512213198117));
#594=CARTESIAN_POINT('',(3.64270408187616,5.,3.81498839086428));
#595=CARTESIAN_POINT('',(3.94183849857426,5.,3.63410530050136));
#596=CARTESIAN_POINT('',(4.08619228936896,5.,3.54360615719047));
#597=CARTESIAN_POINT('',(4.37241977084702,5.,3.35875596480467));
#598=CARTESIAN_POINT('',(4.51429327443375,5.,3.2644046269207));
#599=CARTESIAN_POINT('',(4.79474397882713,5.,3.07330514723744));
#600=CARTESIAN_POINT('',(4.93333850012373,5.,2.97658233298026));
#601=CARTESIAN_POINT('',(5.20862624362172,5.,2.78054405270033));
#602=CARTESIAN_POINT('',(5.34531997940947,5.,2.68122930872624));
#603=CARTESIAN_POINT('',(5.48121637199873,5.,2.58085362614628));
#604=B_SPLINE_CURVE_WITH_KNOTS('',3,(#554,#555,#556,#557,#558,#559,#560,#561,#562,#563,#564,
#565,#566,#567,#568,#569,#570,#571,#572,#573,#574,#575,#576,#577,#578,#579,#580,#581,#582,#583,
#584,#585,#586,#587,#588,#589,#590,#591,#592,#593,#594,#595,#596,#597,#598,#599,#600,#601,#602,
#603),.UNSPECIFIED.,.F.,.F.,(4,2,2,2,2,2,2,2,2,2,2,2,2,2,2,2,2,2,2,2,2,2,2,2,4),(0.,
0.550787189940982,1.10170472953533,1.65687262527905,2.21200221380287,2.80231311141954,
3.39272305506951,3.98133740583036,4.56967302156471,5.10001866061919,5.63039808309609,
6.15060655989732,6.6707071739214,7.16810854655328,7.66555511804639,8.17200736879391,
8.67843078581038,9.21417708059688,9.75016569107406,10.2878542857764,10.825460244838,
11.3365177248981,11.84761359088,12.3546057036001,12.861458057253),.UNSPECIFIED.);
#605=EDGE_CURVE('E294',#551,#40,#604,.F.);
#606=ORIENTED_EDGE('',*,*,#605,.T.);
#607=EDGE_LOOP('',(#509,#544,#553,#606));
#608=FACE_BOUND('',#607,.T.);
#609=ADVANCED_FACE('F209',(#608),#508,.T.);
#610=CARTESIAN_POINT('',(-4.33012701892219,-2.5,5.));
#611=VERTEX_POINT('',#610);
#612=EDGE_CURVE('E174',#542,#611,#549,.T.);
#613=ORIENTED_EDGE('',*,*,#612,.F.);
#614=EDGE_CURVE('E305',#542,#68,#540,.T.);
#615=ORIENTED_EDGE('',*,*,#614,.T.);
#616=ORIENTED_EDGE('',*,*,#83,.F.);
#617=CARTESIAN_POINT('',(-5.7702,-0.00572043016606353,4.22979716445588));
#618=CARTESIAN_POINT('',(-5.72066643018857,-0.0915150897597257,4.27923827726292));
#619=CARTESIAN_POINT('',(-5.67075262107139,-0.177968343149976,4.32715870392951));
#620=CARTESIAN_POINT('',(-5.57009042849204,-0.352320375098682,4.41949696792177));
#621=CARTESIAN_POINT('',(-5.51934160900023,-0.440219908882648,4.46391290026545));
#622=CARTESIAN_POINT('',(-5.36526368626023,-0.707090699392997,4.59158786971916));
#623=CARTESIAN_POINT('',(-5.26063326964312,-0.888315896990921,4.66873317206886));
#624=CARTESIAN_POINT('',(-5.04964011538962,-1.25376676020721,4.8008233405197));
#625=CARTESIAN_POINT('',(-4.94333082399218,-1.43789985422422,4.85609954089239));
#626=CARTESIAN_POINT('',(-4.78212663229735,-1.71711370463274,4.92002857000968));
#627=CARTESIAN_POINT('',(-4.72815538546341,-1.81059464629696,4.93816556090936));
#628=CARTESIAN_POINT('',(-4.61975813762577,-1.99834418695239,4.96770236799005));
#629=CARTESIAN_POINT('',(-4.56533220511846,-2.09261266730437,4.97910318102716));
#630=CARTESIAN_POINT('',(-4.43253200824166,-2.32262935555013,4.99823638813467));
#631=CARTESIAN_POINT('',(-4.35401435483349,-2.45862592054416,5.00223001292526));
#632=CARTESIAN_POINT('',(-4.19712243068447,-2.7303707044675,4.99538895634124));
#633=CARTESIAN_POINT('',(-4.11874821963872,-2.86611882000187,4.98454909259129));
#634=CARTESIAN_POINT('',(-3.96274074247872,-3.13633169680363,4.94868002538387));
#635=CARTESIAN_POINT('',(-3.88510839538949,-3.27079486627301,4.92363508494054));
#636=CARTESIAN_POINT('',(-3.73117872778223,-3.53740887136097,4.86071673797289));
#637=CARTESIAN_POINT('',(-3.65488130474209,-3.66955988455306,4.82284432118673));
#638=CARTESIAN_POINT('',(-3.51977568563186,-3.90356968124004,4.7451338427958));
#639=CARTESIAN_POINT('',(-3.46066177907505,-4.00595797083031,4.7073815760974));
#640=CARTESIAN_POINT('',(-3.3434891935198,-4.20890684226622,4.6258253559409));
#641=CARTESIAN_POINT('',(-3.28543053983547,-4.30946738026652,4.58202125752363));
#642=CARTESIAN_POINT('',(-3.17055191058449,-4.50844300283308,4.48933505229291));
#643=CARTESIAN_POINT('',(-3.11372867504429,-4.60686373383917,4.44046897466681));
#644=CARTESIAN_POINT('',(-3.00112820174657,-4.80189347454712,4.33829282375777));
#645=CARTESIAN_POINT('',(-2.94535036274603,-4.89850352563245,4.28498540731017));
#646=CARTESIAN_POINT('',(-2.89005687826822,-4.99427465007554,4.2297999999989));
#647=B_SPLINE_CURVE_WITH_KNOTS('',3,(#617,#618,#619,#620,#621,#622,#623,#624,#625,#626,#627,
#628,#629,#630,#631,#632,#633,#634,#635,#636,#637,#638,#639,#640,#641,#642,#643,#644,#645,#646),
.UNSPECIFIED.,.F.,.F.,(4,2,2,2,2,2,2,2,2,2,2,2,2,2,4),(0.,0.332137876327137,0.664455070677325,
1.33265140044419,1.99029611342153,2.31847842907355,2.64661216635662,3.11713813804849,
3.58782853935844,4.05904141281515,4.53021793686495,4.90237265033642,5.27453627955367,
5.64555549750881,6.01635434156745),.UNSPECIFIED.);
#648=EDGE_CURVE('E158',#80,#611,#647,.T.);
#649=ORIENTED_EDGE('',*,*,#648,.T.);
#650=EDGE_LOOP('',(#613,#615,#616,#649));
#651=FACE_BOUND('',#650,.T.);
#652=ADVANCED_FACE('F171',(#651),#508,.T.);
#653=ORIENTED_EDGE('',*,*,#100,.F.);
#654=EDGE_CURVE('E299',#93,#551,#604,.F.);
#655=ORIENTED_EDGE('',*,*,#654,.T.);
#656=CARTESIAN_POINT('',(4.33012701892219,2.5,5.));
#657=VERTEX_POINT('',#656);
#658=EDGE_CURVE('E166',#657,#551,#549,.T.);
#659=ORIENTED_EDGE('',*,*,#658,.F.);
#660=CARTESIAN_POINT('',(5.7702,0.0057204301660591,4.22979716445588));
#661=CARTESIAN_POINT('',(5.72066643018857,0.0915150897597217,4.27923827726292));
#662=CARTESIAN_POINT('',(5.67075262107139,0.177968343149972,4.32715870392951));
#663=CARTESIAN_POINT('',(5.57009042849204,0.352320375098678,4.41949696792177));
#664=CARTESIAN_POINT('',(5.51934160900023,0.440219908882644,4.46391290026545));
#665=CARTESIAN_POINT('',(5.36526368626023,0.707090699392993,4.59158786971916));
#666=CARTESIAN_POINT('',(5.26063326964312,0.888315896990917,4.66873317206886));
#667=CARTESIAN_POINT('',(5.04964011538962,1.25376676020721,4.8008233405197));
#668=CARTESIAN_POINT('',(4.94333082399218,1.43789985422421,4.85609954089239));
#669=CARTESIAN_POINT('',(4.78212663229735,1.71711370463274,4.92002857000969));
#670=CARTESIAN_POINT('',(4.72815538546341,1.81059464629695,4.93816556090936));
#671=CARTESIAN_POINT('',(4.61975813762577,1.99834418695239,4.96770236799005));
#672=CARTESIAN_POINT('',(4.56533220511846,2.09261266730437,4.97910318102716));
#673=CARTESIAN_POINT('',(4.43253200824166,2.32262935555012,4.99823638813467));
#674=CARTESIAN_POINT('',(4.35401435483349,2.45862592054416,5.00223001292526));
#675=CARTESIAN_POINT('',(4.19712243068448,2.7303707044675,4.99538895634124));
#676=CARTESIAN_POINT('',(4.11874821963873,2.86611882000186,4.98454909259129));
#677=CARTESIAN_POINT('',(3.96274074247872,3.13633169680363,4.94868002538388));
#678=CARTESIAN_POINT('',(3.88510839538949,3.27079486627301,4.92363508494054));
#679=CARTESIAN_POINT('',(3.73117872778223,3.53740887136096,4.86071673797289));
#680=CARTESIAN_POINT('',(3.65488130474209,3.66955988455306,4.82284432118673));
#681=CARTESIAN_POINT('',(3.51977568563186,3.90356968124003,4.7451338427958));
#682=CARTESIAN_POINT('',(3.46066177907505,4.00595797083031,4.7073815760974));
#683=CARTESIAN_POINT('',(3.3434891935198,4.20890684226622,4.6258253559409));
#684=CARTESIAN_POINT('',(3.28543053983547,4.30946738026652,4.58202125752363));
#685=CARTESIAN_POINT('',(3.17055191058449,4.50844300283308,4.48933505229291));
#686=CARTESIAN_POINT('',(3.11372867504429,4.60686373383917,4.44046897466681));
#687=CARTESIAN_POINT('',(3.00112820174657,4.80189347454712,4.33829282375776));
#688=CARTESIAN_POINT('',(2.94535036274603,4.89850352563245,4.28498540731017));
#689=CARTESIAN_POINT('',(2.89005687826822,4.99427465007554,4.2297999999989));
#690=B_SPLINE_CURVE_WITH_KNOTS('',3,(#660,#661,#662,#663,#664,#665,#666,#667,#668,#669,#670,
#671,#672,#673,#674,#675,#676,#677,#678,#679,#680,#681,#682,#683,#684,#685,#686,#687,#688,#689),
.UNSPECIFIED.,.F.,.F.,(4,2,2,2,2,2,2,2,2,2,2,2,2,2,4),(0.,0.332137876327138,0.664455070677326,
1.33265140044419,1.99029611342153,2.31847842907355,2.64661216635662,3.11713813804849,
3.58782853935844,4.05904141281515,4.53021793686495,4.90237265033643,5.27453627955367,
5.64555549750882,6.01635434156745),.UNSPECIFIED.);
#691=EDGE_CURVE('E301',#657,#99,#690,.T.);
#692=ORIENTED_EDGE('',*,*,#691,.T.);
#693=EDGE_LOOP('',(#653,#655,#659,#692));
#694=FACE_BOUND('',#693,.T.);
#695=ADVANCED_FACE('F314',(#694),#508,.T.);
#696=ORIENTED_EDGE('',*,*,#127,.F.);
#697=EDGE_CURVE('E300',#120,#657,#690,.T.);
#698=ORIENTED_EDGE('',*,*,#697,.T.);
#699=CARTESIAN_POINT('',(4.33012701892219,-2.5,5.));
#700=VERTEX_POINT('',#699);
#701=EDGE_CURVE('E195',#700,#657,#549,.T.);
#702=ORIENTED_EDGE('',*,*,#701,.F.);
#703=CARTESIAN_POINT('',(2.89005687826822,-4.99427465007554,4.2297999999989));
#704=CARTESIAN_POINT('',(2.93959036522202,-4.90848013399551,4.27924095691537));
#705=CARTESIAN_POINT('',(2.98950409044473,-4.82202702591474,4.32716122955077));
#706=CARTESIAN_POINT('',(3.09016611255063,-4.64767528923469,4.41949919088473));
#707=CARTESIAN_POINT('',(3.1409148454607,-4.55977590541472,4.46391497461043));
#708=CARTESIAN_POINT('',(3.294992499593,-4.29290558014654,4.59158950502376));
#709=CARTESIAN_POINT('',(3.39962272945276,-4.11168070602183,4.66873452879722));
#710=CARTESIAN_POINT('',(3.61061549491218,-3.74623051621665,4.80082419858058));
#711=CARTESIAN_POINT('',(3.71692458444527,-3.56209777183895,4.85610017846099));
#712=CARTESIAN_POINT('',(3.87812846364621,-3.28288446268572,4.92002894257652));
#713=CARTESIAN_POINT('',(3.93209960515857,-3.18940370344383,4.93816585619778));
#714=CARTESIAN_POINT('',(4.0404966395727,-3.00165453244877,4.96770253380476));
#715=CARTESIAN_POINT('',(4.09492246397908,-2.9073862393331,4.97910329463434));
#716=CARTESIAN_POINT('',(4.22772254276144,-2.6773697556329,4.99823642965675));
#717=CARTESIAN_POINT('',(4.30624018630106,-2.54137320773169,5.00223002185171));
#718=CARTESIAN_POINT('',(4.46313208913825,-2.26962846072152,4.99538890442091));
#719=CARTESIAN_POINT('',(4.54150628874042,-2.13388036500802,4.98454901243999));
#720=CARTESIAN_POINT('',(4.69751374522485,-1.8636675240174,4.94867989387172));
#721=CARTESIAN_POINT('',(4.7751460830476,-1.72920437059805,4.92363492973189));
#722=CARTESIAN_POINT('',(4.92907573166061,-1.46259039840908,4.86071654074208));
#723=CARTESIAN_POINT('',(5.00537314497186,-1.33043940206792,4.82284410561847));
#724=CARTESIAN_POINT('',(5.14047897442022,-1.09642924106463,4.74513346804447));
#725=CARTESIAN_POINT('',(5.19959309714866,-0.994040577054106,4.70738103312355));
#726=CARTESIAN_POINT('',(5.31676610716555,-0.791090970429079,4.62582443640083));
#727=CARTESIAN_POINT('',(5.37482496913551,-0.690530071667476,4.582020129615));
#728=CARTESIAN_POINT('',(5.48970400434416,-0.491553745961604,4.48933347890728));
#729=CARTESIAN_POINT('',(5.5465274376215,-0.393132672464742,4.44046716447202));
#730=CARTESIAN_POINT('',(5.65912829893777,-0.198102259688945,4.33829051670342));
#731=CARTESIAN_POINT('',(5.71490632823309,-0.101491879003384,4.28498284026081));
#732=CARTESIAN_POINT('',(5.7702,-0.00572043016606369,4.22979716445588));
#733=B_SPLINE_CURVE_WITH_KNOTS('',3,(#703,#704,#705,#706,#707,#708,#709,#710,#711,#712,#713,
#714,#715,#716,#717,#718,#719,#720,#721,#722,#723,#724,#725,#726,#727,#728,#729,#730,#731,#732),
.UNSPECIFIED.,.F.,.F.,(4,2,2,2,2,2,2,2,2,2,2,2,2,2,4),(0.,0.332137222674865,0.664453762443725,
1.33264875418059,1.99029213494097,2.31847378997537,2.64660686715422,3.11713277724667,
3.58782311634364,4.05903594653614,4.53021242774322,4.90236852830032,5.27453354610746,
5.64555413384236,6.01635434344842),.UNSPECIFIED.);
#734=EDGE_CURVE('E462',#700,#126,#733,.T.);
#735=ORIENTED_EDGE('',*,*,#734,.T.);
#736=EDGE_LOOP('',(#696,#698,#702,#735));
#737=FACE_BOUND('',#736,.T.);
#738=ADVANCED_FACE('F507',(#737),#508,.T.);
#739=ORIENTED_EDGE('',*,*,#154,.F.);
#740=EDGE_CURVE('E461',#147,#700,#733,.T.);
#741=ORIENTED_EDGE('',*,*,#740,.T.);
#742=CARTESIAN_POINT('',(0.,-5.,5.));
#743=VERTEX_POINT('',#742);
#744=EDGE_CURVE('E187',#743,#700,#549,.T.);
#745=ORIENTED_EDGE('',*,*,#744,.F.);
#746=CARTESIAN_POINT('',(-6.02299831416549,-5.,2.17206868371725));
#747=CARTESIAN_POINT('',(-5.87748004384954,-5.,2.28400879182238));
#748=CARTESIAN_POINT('',(-5.73117753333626,-5.,2.39494543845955));
#749=CARTESIAN_POINT('',(-5.43668354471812,-5.,2.61435341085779));
#750=CARTESIAN_POINT('',(-5.28849162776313,-5.,2.72282414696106));
#751=CARTESIAN_POINT('',(-4.98881537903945,-5.,2.93761383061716));
#752=CARTESIAN_POINT('',(-4.837314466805,-5.,3.04390972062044));
#753=CARTESIAN_POINT('',(-4.53179094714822,-5.,3.2528010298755));
#754=CARTESIAN_POINT('',(-4.37776851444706,-5.,3.35539670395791));
#755=CARTESIAN_POINT('',(-4.05692316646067,-5.,3.56240295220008));
#756=CARTESIAN_POINT('',(-3.88990763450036,-5.,3.66651648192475));
#757=CARTESIAN_POINT('',(-3.55195456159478,-5.,3.86827943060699));
#758=CARTESIAN_POINT('',(-3.38101636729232,-5.,3.96592776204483));
#759=CARTESIAN_POINT('',(-3.03517153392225,-5.,4.15268061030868));
#760=CARTESIAN_POINT('',(-2.86027854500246,-5.,4.24181020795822));
#761=CARTESIAN_POINT('',(-2.5055493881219,-5.,4.40952866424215));
#762=CARTESIAN_POINT('',(-2.32571560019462,-5.,4.48812249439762));
#763=CARTESIAN_POINT('',(-1.97870613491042,-5.,4.62483159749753));
#764=CARTESIAN_POINT('',(-1.81202993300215,-5.,4.68420180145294));
#765=CARTESIAN_POINT('',(-1.47443232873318,-5.,4.78960068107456));
#766=CARTESIAN_POINT('',(-1.3035106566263,-5.,4.8356285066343));
#767=CARTESIAN_POINT('',(-0.961419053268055,-5.,4.91108446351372));
#768=CARTESIAN_POINT('',(-0.79031673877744,-5.,4.94081399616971));
#769=CARTESIAN_POINT('',(-0.44598784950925,-5.,4.98305336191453));
#770=CARTESIAN_POINT('',(-0.272761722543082,-5.,4.99556676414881));
#771=CARTESIAN_POINT('',(0.0664794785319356,-5.,5.00230866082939));
#772=CARTESIAN_POINT('',(0.232479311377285,-5.,4.99731134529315));
#773=CARTESIAN_POINT('',(0.56318295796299,-5.,4.97108467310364));
#774=CARTESIAN_POINT('',(0.727886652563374,-5.,4.94985384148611));
#775=CARTESIAN_POINT('',(1.05759729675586,-5.,4.89199950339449));
#776=CARTESIAN_POINT('',(1.22255575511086,-5.,4.85510428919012));
#777=CARTESIAN_POINT('',(1.54884022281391,-5.,4.76796766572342));
#778=CARTESIAN_POINT('',(1.71016643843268,-5.,4.71772701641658));
#779=CARTESIAN_POINT('',(2.03810171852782,-5.,4.60287986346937));
#780=CARTESIAN_POINT('',(2.20447580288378,-5.,4.53760998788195));
#781=CARTESIAN_POINT('',(2.53294434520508,-5.,4.39698673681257));
#782=CARTESIAN_POINT('',(2.69503683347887,-5.,4.32162881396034));
#783=CARTESIAN_POINT('',(3.01570779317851,-5.,4.16261658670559));
#784=CARTESIAN_POINT('',(3.17427348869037,-5.,4.07893672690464));
#785=CARTESIAN_POINT('',(3.48777135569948,-5.,3.90512213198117));
#786=CARTESIAN_POINT('',(3.64270408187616,-5.,3.81498839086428));
#787=CARTESIAN_POINT('',(3.94183849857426,-5.,3.63410530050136));
#788=CARTESIAN_POINT('',(4.08619228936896,-5.,3.54360615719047));
#789=CARTESIAN_POINT('',(4.37241977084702,-5.,3.35875596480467));
#790=CARTESIAN_POINT('',(4.51429327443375,-5.,3.2644046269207));
#791=CARTESIAN_POINT('',(4.79474397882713,-5.,3.07330514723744));
#792=CARTESIAN_POINT('',(4.93333850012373,-5.,2.97658233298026));
#793=CARTESIAN_POINT('',(5.20862624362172,-5.,2.78054405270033));
#794=CARTESIAN_POINT('',(5.34531997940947,-5.,2.68122930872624));
#795=CARTESIAN_POINT('',(5.48121637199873,-5.,2.58085362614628));
#796=B_SPLINE_CURVE_WITH_KNOTS('',3,(#746,#747,#748,#749,#750,#751,#752,#753,#754,#755,#756,
#757,#758,#759,#760,#761,#762,#763,#764,#765,#766,#767,#768,#769,#770,#771,#772,#773,#774,#775,
#776,#777,#778,#779,#780,#781,#782,#783,#784,#785,#786,#787,#788,#789,#790,#791,#792,#793,#794,
#795),.UNSPECIFIED.,.F.,.F.,(4,2,2,2,2,2,2,2,2,2,2,2,2,2,2,2,2,2,2,2,2,2,2,2,4),(0.,
0.550787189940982,1.10170472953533,1.65687262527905,2.21200221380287,2.80231311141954,
3.39272305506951,3.98133740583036,4.56967302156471,5.10001866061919,5.63039808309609,
6.15060655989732,6.6707071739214,7.16810854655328,7.66555511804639,8.17200736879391,
8.67843078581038,9.21417708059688,9.75016569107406,10.2878542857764,10.825460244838,
11.3365177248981,11.84761359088,12.3546057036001,12.861458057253),.UNSPECIFIED.);
#797=EDGE_CURVE('E178',#743,#153,#796,.T.);
#798=ORIENTED_EDGE('',*,*,#797,.T.);
#799=EDGE_LOOP('',(#739,#741,#745,#798));
#800=FACE_BOUND('',#799,.T.);
#801=ADVANCED_FACE('F460',(#800),#508,.T.);
#802=ORIENTED_EDGE('',*,*,#181,.F.);
#803=EDGE_CURVE('E183',#174,#743,#796,.T.);
#804=ORIENTED_EDGE('',*,*,#803,.T.);
#805=EDGE_CURVE('E181',#611,#743,#549,.T.);
#806=ORIENTED_EDGE('',*,*,#805,.F.);
#807=EDGE_CURVE('E155',#611,#180,#647,.T.);
#808=ORIENTED_EDGE('',*,*,#807,.T.);
#809=EDGE_LOOP('',(#802,#804,#806,#808));
#810=FACE_BOUND('',#809,.T.);
#811=ADVANCED_FACE('F182',(#810),#508,.T.);
#812=CARTESIAN_POINT('',(0.,0.,5.));
#813=DIRECTION('',(0.,0.,1.));
#814=DIRECTION('',(1.,0.,0.));
#815=AXIS2_PLACEMENT_3D('',#812,#813,#814);
#816=PLANE('',#815);
#817=ORIENTED_EDGE('',*,*,#658,.T.);
#818=ORIENTED_EDGE('',*,*,#552,.T.);
#819=ORIENTED_EDGE('',*,*,#612,.T.);
#820=ORIENTED_EDGE('',*,*,#805,.T.);
#821=ORIENTED_EDGE('',*,*,#744,.T.);
#822=ORIENTED_EDGE('',*,*,#701,.T.);
#823=EDGE_LOOP('',(#817,#818,#819,#820,#821,#822));
#824=FACE_BOUND('',#823,.T.);
#825=CARTESIAN_POINT('',(0.,0.,5.));
#826=DIRECTION('',(0.,0.,1.));
#827=DIRECTION('',(1.,0.,0.));
#828=AXIS2_PLACEMENT_3D('',#825,#826,#827);
#829=CIRCLE('',#828,4.5);
#830=CARTESIAN_POINT('',(4.5,0.,5.));
#831=VERTEX_POINT('',#830);
#832=EDGE_CURVE('E365',#831,#831,#829,.T.);
#833=ORIENTED_EDGE('',*,*,#832,.F.);
#834=EDGE_LOOP('',(#833));
#835=FACE_BOUND('',#834,.T.);
#836=ADVANCED_FACE('F190',(#824,#835),#816,.T.);
#837=CARTESIAN_POINT('',(0.,0.,0.));
#838=DIRECTION('',(0.,0.,1.));
#839=DIRECTION('',(1.,0.,0.));
#840=AXIS2_PLACEMENT_3D('',#837,#838,#839);
#841=PLANE('',#840);
#842=CARTESIAN_POINT('',(0.,0.,0.));
#843=DIRECTION('',(0.,0.,1.));
#844=DIRECTION('',(1.,0.,0.));
#845=AXIS2_PLACEMENT_3D('',#842,#843,#844);
#846=CIRCLE('',#845,2.5);
#847=CARTESIAN_POINT('',(2.5,0.,0.));
#848=VERTEX_POINT('',#847);
#849=EDGE_CURVE('E424',#848,#848,#846,.T.);
#850=ORIENTED_EDGE('',*,*,#849,.T.);
#851=EDGE_LOOP('',(#850));
#852=FACE_BOUND('',#851,.T.);
#853=ORIENTED_EDGE('',*,*,#433,.T.);
#854=ORIENTED_EDGE('',*,*,#494,.T.);
#855=ORIENTED_EDGE('',*,*,#244,.T.);
#856=ORIENTED_EDGE('',*,*,#284,.T.);
#857=ORIENTED_EDGE('',*,*,#347,.T.);
#858=ORIENTED_EDGE('',*,*,#390,.T.);
#859=EDGE_LOOP('',(#853,#854,#855,#856,#857,#858));
#860=FACE_BOUND('',#859,.T.);
#861=ADVANCED_FACE('F393',(#852,#860),#841,.F.);
#862=CARTESIAN_POINT('',(0.,0.,6.));
#863=DIRECTION('',(0.,0.,1.));
#864=DIRECTION('',(1.,0.,0.));
#865=AXIS2_PLACEMENT_3D('',#862,#863,#864);
#866=PLANE('',#865);
#867=CARTESIAN_POINT('',(0.,0.,6.));
#868=DIRECTION('',(0.,0.,1.));
#869=DIRECTION('',(1.,0.,0.));
#870=AXIS2_PLACEMENT_3D('',#867,#868,#869);
#871=CIRCLE('',#870,2.5);
#872=CARTESIAN_POINT('',(2.5,0.,6.));
#873=VERTEX_POINT('',#872);
#874=EDGE_CURVE('E426',#873,#873,#871,.T.);
#875=ORIENTED_EDGE('',*,*,#874,.F.);
#876=EDGE_LOOP('',(#875));
#877=FACE_BOUND('',#876,.T.);
#878=CARTESIAN_POINT('',(0.,0.,6.));
#879=DIRECTION('',(0.,0.,1.));
#880=DIRECTION('',(1.,0.,0.));
#881=AXIS2_PLACEMENT_3D('',#878,#879,#880);
#882=CIRCLE('',#881,3.5);
#883=CARTESIAN_POINT('',(3.5,0.,6.));
#884=VERTEX_POINT('',#883);
#885=EDGE_CURVE('E11',#884,#884,#882,.T.);
#886=ORIENTED_EDGE('',*,*,#885,.T.);
#887=EDGE_LOOP('',(#886));
#888=FACE_BOUND('',#887,.T.);
#889=ADVANCED_FACE('F216',(#877,#888),#866,.T.);
#890=CARTESIAN_POINT('',(-5.77350269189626,0.,0.));
#891=DIRECTION('',(-0.866025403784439,-0.5,0.));
#892=DIRECTION('',(0.5,-0.866025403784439,0.));
#893=AXIS2_PLACEMENT_3D('',#890,#891,#892);
#894=PLANE('',#893);
#895=ORIENTED_EDGE('',*,*,#189,.T.);
#896=ORIENTED_EDGE('',*,*,#807,.F.);
#897=ORIENTED_EDGE('',*,*,#648,.F.);
#898=ORIENTED_EDGE('',*,*,#81,.T.);
#899=ORIENTED_EDGE('',*,*,#277,.F.);
#900=ORIENTED_EDGE('',*,*,#499,.F.);
#901=EDGE_LOOP('',(#895,#896,#897,#898,#899,#900));
#902=FACE_BOUND('',#901,.T.);
#903=ADVANCED_FACE('F157',(#902),#894,.T.);
#904=CARTESIAN_POINT('',(-2.88675134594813,-5.,0.));
#905=DIRECTION('',(0.,-1.,0.));
#906=DIRECTION('',(0.,0.,-1.));
#907=AXIS2_PLACEMENT_3D('',#904,#905,#906);
#908=PLANE('',#907);
#909=ORIENTED_EDGE('',*,*,#162,.T.);
#910=ORIENTED_EDGE('',*,*,#797,.F.);
#911=ORIENTED_EDGE('',*,*,#803,.F.);
#912=ORIENTED_EDGE('',*,*,#177,.T.);
#913=ORIENTED_EDGE('',*,*,#496,.F.);
#914=ORIENTED_EDGE('',*,*,#489,.F.);
#915=EDGE_LOOP('',(#909,#910,#911,#912,#913,#914));
#916=FACE_BOUND('',#915,.T.);
#917=ADVANCED_FACE('F215',(#916),#908,.T.);
#918=CARTESIAN_POINT('',(5.77350269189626,0.,0.));
#919=DIRECTION('',(0.866025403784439,-0.5,0.));
#920=DIRECTION('',(0.5,0.866025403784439,0.));
#921=AXIS2_PLACEMENT_3D('',#918,#919,#920);
#922=PLANE('',#921);
#923=ORIENTED_EDGE('',*,*,#135,.T.);
#924=ORIENTED_EDGE('',*,*,#734,.F.);
#925=ORIENTED_EDGE('',*,*,#740,.F.);
#926=ORIENTED_EDGE('',*,*,#150,.T.);
#927=ORIENTED_EDGE('',*,*,#435,.F.);
#928=ORIENTED_EDGE('',*,*,#426,.F.);
#929=EDGE_LOOP('',(#923,#924,#925,#926,#927,#928));
#930=FACE_BOUND('',#929,.T.);
#931=ADVANCED_FACE('F466',(#930),#922,.T.);
#932=CARTESIAN_POINT('',(2.88675134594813,5.,0.));
#933=DIRECTION('',(0.866025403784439,0.5,0.));
#934=DIRECTION('',(-0.5,0.866025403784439,0.));
#935=AXIS2_PLACEMENT_3D('',#932,#933,#934);
#936=PLANE('',#935);
#937=ORIENTED_EDGE('',*,*,#108,.T.);
#938=ORIENTED_EDGE('',*,*,#691,.F.);
#939=ORIENTED_EDGE('',*,*,#697,.F.);
#940=ORIENTED_EDGE('',*,*,#123,.T.);
#941=ORIENTED_EDGE('',*,*,#392,.F.);
#942=ORIENTED_EDGE('',*,*,#383,.F.);
#943=EDGE_LOOP('',(#937,#938,#939,#940,#941,#942));
#944=FACE_BOUND('',#943,.T.);
#945=ADVANCED_FACE('F288',(#944),#936,.T.);
#946=CARTESIAN_POINT('',(-2.88675134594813,5.,0.));
#947=DIRECTION('',(0.,1.,0.));
#948=DIRECTION('',(0.,0.,1.));
#949=AXIS2_PLACEMENT_3D('',#946,#947,#948);
#950=PLANE('',#949);
#951=ORIENTED_EDGE('',*,*,#49,.T.);
#952=ORIENTED_EDGE('',*,*,#605,.F.);
#953=ORIENTED_EDGE('',*,*,#654,.F.);
#954=ORIENTED_EDGE('',*,*,#96,.T.);
#955=ORIENTED_EDGE('',*,*,#349,.F.);
#956=ORIENTED_EDGE('',*,*,#340,.F.);
#957=EDGE_LOOP('',(#951,#952,#953,#954,#955,#956));
#958=FACE_BOUND('',#957,.T.);
#959=ADVANCED_FACE('F284',(#958),#950,.T.);
#960=CARTESIAN_POINT('',(-2.88675134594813,5.,0.));
#961=DIRECTION('',(-0.866025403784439,0.5,0.));
#962=DIRECTION('',(-0.5,-0.866025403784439,0.));
#963=AXIS2_PLACEMENT_3D('',#960,#961,#962);
#964=PLANE('',#963);
#965=ORIENTED_EDGE('',*,*,#69,.T.);
#966=ORIENTED_EDGE('',*,*,#614,.F.);
#967=ORIENTED_EDGE('',*,*,#543,.F.);
#968=ORIENTED_EDGE('',*,*,#32,.T.);
#969=ORIENTED_EDGE('',*,*,#286,.F.);
#970=ORIENTED_EDGE('',*,*,#235,.F.);
#971=EDGE_LOOP('',(#965,#966,#967,#968,#969,#970));
#972=FACE_BOUND('',#971,.T.);
#973=ADVANCED_FACE('F219',(#972),#964,.T.);
#974=CARTESIAN_POINT('',(0.,0.,5.));
#975=DIRECTION('',(0.,0.,1.));
#976=DIRECTION('',(1.,0.,0.));
#977=AXIS2_PLACEMENT_3D('',#974,#975,#976);
#978=TOROIDAL_SURFACE('',#977,3.5,1.);
#979=ORIENTED_EDGE('',*,*,#832,.T.);
#980=EDGE_LOOP('',(#979));
#981=FACE_BOUND('',#980,.T.);
#982=ORIENTED_EDGE('',*,*,#885,.F.);
#983=EDGE_LOOP('',(#982));
#984=FACE_BOUND('',#983,.T.);
#985=ADVANCED_FACE('F289',(#981,#984),#978,.T.);
#986=CARTESIAN_POINT('',(0.,0.,0.));
#987=DIRECTION('',(0.,0.,1.));
#988=DIRECTION('',(1.,0.,0.));
#989=AXIS2_PLACEMENT_3D('',#986,#987,#988);
#990=CYLINDRICAL_SURFACE('',#989,2.5);
#991=ORIENTED_EDGE('',*,*,#849,.F.);
#992=EDGE_LOOP('',(#991));
#993=FACE_BOUND('',#992,.T.);
#994=ORIENTED_EDGE('',*,*,#874,.T.);
#995=EDGE_LOOP('',(#994));
#996=FACE_BOUND('',#995,.T.);
#997=ADVANCED_FACE('F432',(#993,#996),#990,.F.);
#998=CLOSED_SHELL('',(#60,#87,#114,#141,#168,#195,#281,#344,#387,#430,#493,#503,#609,#652,#695,
#738,#801,#811,#836,#861,#889,#903,#917,#931,#945,#959,#973,#985,#997));
#999=MANIFOLD_SOLID_BREP('B2',#998);
#1000=ADVANCED_BREP_SHAPE_REPRESENTATION('',(#18,#999),#14);
#1001=SHAPE_DEFINITION_REPRESENTATION(#9,#1000);
ENDSEC;
END-ISO-10303-21;
